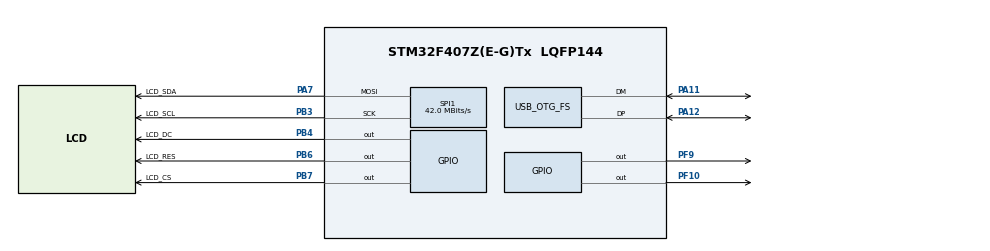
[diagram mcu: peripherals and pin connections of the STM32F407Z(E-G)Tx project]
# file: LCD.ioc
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Dma.Request0=SPI1_TX
Dma.SPI1_TX.0.Direction=DMA_MEMORY_TO_PERIPH
Dma.SPI1_TX.0.FIFOMode=DMA_FIFOMODE_DISABLE
Dma.SPI1_TX.0.Instance=DMA2_Stream3
Dma.SPI1_TX.0.MemDataAlignment=DMA_MDATAALIGN_BYTE
Dma.SPI1_TX.0.MemInc=DMA_MINC_ENABLE
Dma.SPI1_TX.0.Mode=DMA_NORMAL
Dma.SPI1_TX.0.PeriphDataAlignment=DMA_PDATAALIGN_BYTE
Dma.SPI1_TX.0.PeriphInc=DMA_PINC_DISABLE
Dma.SPI1_TX.0.Priority=DMA_PRIORITY_LOW
Mcu.Family=STM32F4
Mcu.Name=STM32F407Z(E-G)Tx
Mcu.Package=LQFP144
NVIC.DMA2_Stream3_IRQn=true\:0\:0\:false\:false\:true\:false\:true\:true
NVIC.OTG_FS_IRQn=true\:3\:0\:true\:false\:true\:true\:true\:true
NVIC.PriorityGroup=NVIC_PRIORITYGROUP_4
NVIC.TIM8_TRG_COM_TIM14_IRQn=true\:0\:0\:false\:false\:true\:false\:true\:true
NVIC.TimeBase=TIM8_TRG_COM_TIM14_IRQn
NVIC.TimeBaseIP=TIM14
PA11.Mode=Device_Only
PA11.Signal=USB_OTG_FS_DM
PA12.Mode=Device_Only
PA12.Signal=USB_OTG_FS_DP
PA13.Mode=Serial_Wire
PA13.Signal=SYS_JTMS-SWDIO
PA14.Mode=Serial_Wire
PA14.Signal=SYS_JTCK-SWCLK
PA7.GPIO_Label=LCD_SDA
PA7.Mode=TX_Only_Simplex_Unidirect_Master
PA7.Signal=SPI1_MOSI
PB3.GPIO_Label=LCD_SCL
PB3.Mode=TX_Only_Simplex_Unidirect_Master
PB3.Signal=SPI1_SCK
PB4.GPIO_Label=LCD_DC
PB4.GPIO_Speed=GPIO_SPEED_FREQ_VERY_HIGH
PB4.Signal=GPIO_Output
PB6.GPIO_Label=LCD_RES
PB6.GPIO_Speed=GPIO_SPEED_FREQ_VERY_HIGH
PB6.Signal=GPIO_Output
PB7.GPIO_Label=LCD_CS
PB7.GPIO_Speed=GPIO_SPEED_FREQ_VERY_HIGH
PB7.Signal=GPIO_Output
PF10.Signal=GPIO_Output
PF9.Signal=GPIO_Output
PH0-OSC_IN.Mode=HSE-External-Oscillator
PH0-OSC_IN.Signal=RCC_OSC_IN
PH1-OSC_OUT.Mode=HSE-External-Oscillator
PH1-OSC_OUT.Signal=RCC_OSC_OUT
ProjectManager.HeapSize=0x200
ProjectManager.StackSize=0x400
ProjectManager.TargetToolchain=MDK-ARM V5.27
RCC.48MHZClocksFreq_Value=48000000
RCC.AHBFreq_Value=168000000
RCC.APB1CLKDivider=RCC_HCLK_DIV4
RCC.APB1Freq_Value=42000000
RCC.APB1TimFreq_Value=84000000
RCC.APB2CLKDivider=RCC_HCLK_DIV2
RCC.APB2Freq_Value=84000000
RCC.APB2TimFreq_Value=168000000
RCC.CortexFreq_Value=168000000
RCC.HCLKFreq_Value=168000000
RCC.HSE_VALUE=8000000
RCC.HSI_VALUE=16000000
RCC.LSE_VALUE=32768
RCC.PLLM=4
RCC.PLLN=168
RCC.PLLQ=7
RCC.SYSCLKFreq_VALUE=168000000
RCC.SYSCLKSource=RCC_SYSCLKSOURCE_PLLCLK
RCC.VCOOutputFreq_Value=336000000
SPI1.CalculateBaudRate=42.0 MBits/s
SPI1.Direction=SPI_DIRECTION_2LINES
SPI1.Mode=SPI_MODE_MASTER
SPI1.VirtualType=VM_MASTER
USB_DEVICE.APP_RX_DATA_SIZE-CDC_FS=4
USB_DEVICE.APP_TX_DATA_SIZE-CDC_FS=4
USB_DEVICE.CLASS_NAME_FS=CDC
USB_DEVICE.VID-CDC_FS=4097
USB_DEVICE.VirtualMode-CDC_FS=Cdc
USB_DEVICE.VirtualModeFS=Cdc_FS
USB_OTG_FS.VirtualMode=Device_Only
VP_SYS_VS_tim14.Mode=TIM14
VP_USB_DEVICE_VS_USB_DEVICE_CDC_FS.Mode=CDC_FS
board=custom

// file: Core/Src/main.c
/* USER CODE BEGIN Header */
/**
  ******************************************************************************
  * @file           : main.c
  * @brief          : Main program body
  ******************************************************************************
  * @attention
  *
  * <h2><center>&copy; Copyright (c) 2024 STMicroelectronics.
  * All rights reserved.</center></h2>
  *
  * This software component is licensed by ST under BSD 3-Clause license,
  * the "License"; You may not use this file except in compliance with the
  * License. You may obtain a copy of the License at:
  *                        opensource.org/licenses/BSD-3-Clause
  *
  ******************************************************************************
  */
/* USER CODE END Header */
#include "main.h"
#include "dma.h"
#include "spi.h"
#include "usb_device.h"
#include "gpio.h"

/* USER CODE BEGIN Includes */
#include "screen.h"
#include "image.h"
#include "usbd_cdc_if.h"
#include "User_usb.h"
/* USER CODE END Includes */

void SystemClock_Config(void);
/* USER CODE BEGIN PFP */
extern uint8_t gImage_1[4][43200];
extern uint8_t gImage_2[4][43200];

/* USER CODE END PFP */

/* USER CODE BEGIN 0 */
int cnt=0;
int cnt26=0;
extern USBD_HandleTypeDef hUsbDeviceFS;
extern struct UsbBuffer_t usbBuffer;
int screen_number=4;
/* USER CODE END 0 */

int main(void)
{

  /* MCU Configuration--------------------------------------------------------*/

  /* Reset of all peripherals, Initializes the Flash interface and the Systick. */
  HAL_Init();

  /* Configure the system clock */
  SystemClock_Config();

  /* Initialize all configured peripherals */
  MX_GPIO_Init();
  MX_DMA_Init();
  MX_SPI1_Init();
  MX_USB_DEVICE_Init();
  /* USER CODE BEGIN 2 */
	screen_init(2);
	Screen_SetWindow(0, 239, 0, 239);

  /* USER CODE END 2 */

  /* Infinite loop */
  while (1)
  {

    /* USER CODE BEGIN 3 */

//		if(cnt==0)
//		{
//			for (int p = 0; p < 4; p++)
//			{
//			if (p == 0)
//					Screen_WriteFrameBuffer(gImage_1[0],43200,0);
//			else
//					Screen_WriteFrameBuffer(gImage_1[p],43200, true);
//			}
//			cnt=2;
//		}
//		else if(cnt==1){
//			for (int p = 0; p < 4; p++)
//			{
//			if (p == 0)
//					Screen_WriteFrameBuffer(gImage_2[0],43200,0);
//			else
//					Screen_WriteFrameBuffer(gImage_2[p],43200, true);
//			}
//		}

		if(cnt==0)
		{
			for (int p = 0; p < 4; p++)
			{
				//ReceiveUsbPacketUntilSizeIs(2);
			if (p == 0 && screen_number==4)
			{
				if(usbBuffer.rxDataOffset==43200)
				{
					Screen_WriteFrameBuffer(usbBuffer.rxData[0],43200,0);
					usbBuffer.rxDataOffset=0;
				}
			}
			else
				if(usbBuffer.rxDataOffset==43200)
				{
					Screen_WriteFrameBuffer(usbBuffer.rxData[0],43200, true);
					screen_number--;
					usbBuffer.rxDataOffset=0;
				}
			}
		}
//		else{
//			for (int p = 0; p < 4; p++)
//			{
//			if (p == 0)
//					Screen_WriteFrameBuffer(GetLcdBufferPtr(),43200,0);
//			else
//					Screen_WriteFrameBuffer(GetLcdBufferPtr(),43200, true);
//			}
//		}

		//HAL_Delay(1);
//		HAL_GPIO_TogglePin(GPIOF,GPIO_PIN_9);
//		HAL_GPIO_TogglePin(GPIOF,GPIO_PIN_10);
//		HAL_Delay(1000);
  }
  /* USER CODE END 3 */
}

void SystemClock_Config(void)
{
  RCC_OscInitTypeDef RCC_OscInitStruct = {0};
  RCC_ClkInitTypeDef RCC_ClkInitStruct = {0};

  /** Configure the main internal regulator output voltage
  */
  __HAL_RCC_PWR_CLK_ENABLE();
  __HAL_PWR_VOLTAGESCALING_CONFIG(PWR_REGULATOR_VOLTAGE_SCALE1);
  /** Initializes the RCC Oscillators according to the specified parameters
  * in the RCC_OscInitTypeDef structure.
  */
  RCC_OscInitStruct.OscillatorType = RCC_OSCILLATORTYPE_HSE;
  RCC_OscInitStruct.HSEState = RCC_HSE_ON;
  RCC_OscInitStruct.PLL.PLLState = RCC_PLL_ON;
  RCC_OscInitStruct.PLL.PLLSource = RCC_PLLSOURCE_HSE;
  RCC_OscInitStruct.PLL.PLLM = 4;
  RCC_OscInitStruct.PLL.PLLN = 168;
  RCC_OscInitStruct.PLL.PLLP = RCC_PLLP_DIV2;
  RCC_OscInitStruct.PLL.PLLQ = 7;
  if (HAL_RCC_OscConfig(&RCC_OscInitStruct) != HAL_OK)
  {
    Error_Handler();
  }
  /** Initializes the CPU, AHB and APB buses clocks
  */
  RCC_ClkInitStruct.ClockType = RCC_CLOCKTYPE_HCLK|RCC_CLOCKTYPE_SYSCLK
                              |RCC_CLOCKTYPE_PCLK1|RCC_CLOCKTYPE_PCLK2;
  RCC_ClkInitStruct.SYSCLKSource = RCC_SYSCLKSOURCE_PLLCLK;
  RCC_ClkInitStruct.AHBCLKDivider = RCC_SYSCLK_DIV1;
  RCC_ClkInitStruct.APB1CLKDivider = RCC_HCLK_DIV4;
  RCC_ClkInitStruct.APB2CLKDivider = RCC_HCLK_DIV1;//chaochao

  if (HAL_RCC_ClockConfig(&RCC_ClkInitStruct, FLASH_LATENCY_5) != HAL_OK)
  {
    Error_Handler();
  }
}

/* USER CODE BEGIN 4 */
//int cnt22=0;
//extern USBD_HandleTypeDef hUsbDeviceFS;

// int8_t CDC_Receive_FS(uint8_t* Buf, uint32_t *Len)
//{
//	cnt22++;
//  CDC_Transmit_FS(Buf,*Len);
//  USBD_CDC_SetRxBuffer(&hUsbDeviceFS, &Buf[0]);
//  USBD_CDC_ReceivePacket(&hUsbDeviceFS);
//  return (USBD_OK);
//}
/* USER CODE END 4 */

 /**
  * @brief  Period elapsed callback in non blocking mode
  * @note   This function is called  when TIM14 interrupt took place, inside
  * HAL_TIM_IRQHandler(). It makes a direct call to HAL_IncTick() to increment
  * a global variable "uwTick" used as application time base.
  * @param  htim : TIM handle
  * @retval None
  */
void HAL_TIM_PeriodElapsedCallback(TIM_HandleTypeDef *htim)
{
  if (htim->Instance == TIM14) {
    HAL_IncTick();
  }
}

void Error_Handler(void)
{
  __disable_irq();
  while (1)
  {
  }
}

/************************ (C) COPYRIGHT STMicroelectronics *****END OF FILE****/
